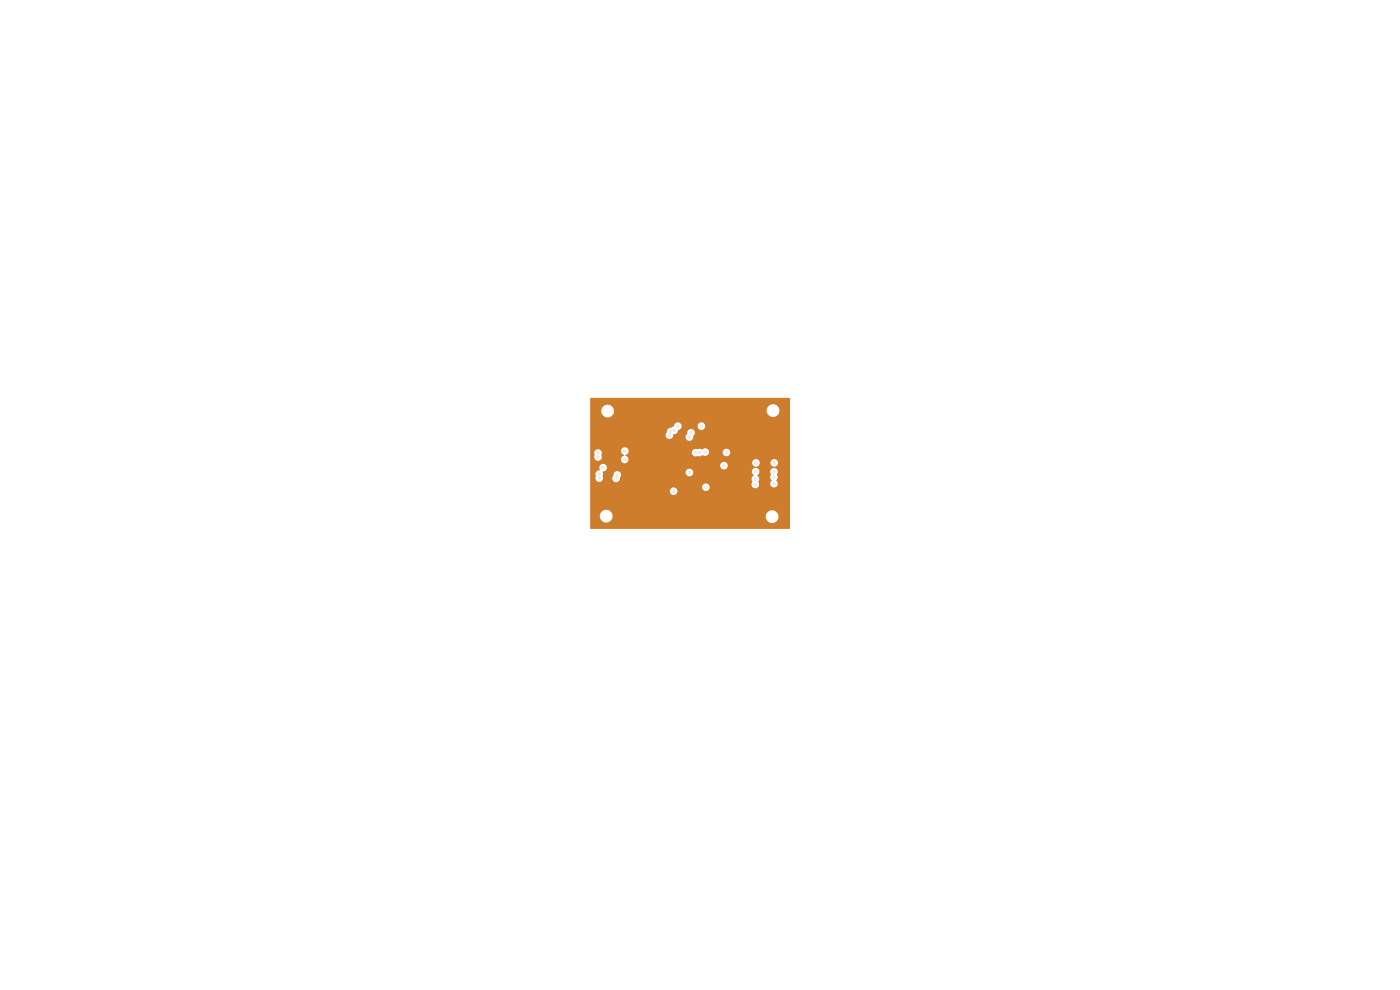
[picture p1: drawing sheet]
<svg xmlns="http://www.w3.org/2000/svg" width="297mm" height="210mm" viewBox="0 0 297 210" stroke-linecap="round" stroke-linejoin="round" font-family="sans-serif">
<g fill="#ececec" stroke="#ececec" stroke-width=".21">
<circle cx="143" cy="91.3" r=".3"/>
<circle cx="149.6" cy="95.9" r=".3"/>
<circle cx="137.2" cy="85" r=".3"/>
<circle cx="152.3" cy="103.2" r=".3"/>
<circle cx="139.2" cy="106.2" r=".3"/>
<circle cx="132" cy="109.2" r=".3"/>
<circle cx="141.4" cy="88.6" r=".3"/>
<circle cx="138.4" cy="86.2" r=".3"/>
<circle cx="151.6" cy="91.2" r=".3"/>
<circle cx="154.6" cy="87.4" r=".3"/>
<circle cx="159" cy="111.6" r=".3"/>
<circle cx="161.4" cy="108" r=".3"/>
<circle cx="160" cy="89.2" r=".3"/>
<circle cx="159.4" cy="89.2" r=".3"/>
<circle cx="127" cy="90.4" r=".3"/>
<circle cx="143.8" cy="86.2" r=".3"/>
<circle cx="138.6" cy="108" r=".3"/>
<circle cx="148.8" cy="110.4" r=".3"/>
<circle cx="137.2" cy="86.8" r=".3"/>
<circle cx="138.4" cy="88" r=".3"/>
<circle cx="126.4" cy="85" r=".3"/>
<circle cx="149.8" cy="85.6" r=".3"/>
<circle cx="139.8" cy="105.6" r=".3"/>
<circle cx="154.7" cy="103.2" r=".3"/>
<circle cx="134.4" cy="109.2" r=".3"/>
<circle cx="140.8" cy="89.2" r=".3"/>
<circle cx="155.8" cy="85" r=".3"/>
<circle cx="154.6" cy="89.2" r=".3"/>
<circle cx="151" cy="86.8" r=".3"/>
<circle cx="149.8" cy="88.6" r=".3"/>
<circle cx="139" cy="85" r=".3"/>
<circle cx="136.2" cy="110.4" r=".3"/>
<circle cx="161.2" cy="85" r=".3"/>
<circle cx="143.2" cy="86.2" r=".3"/>
<circle cx="129.6" cy="106.8" r=".3"/>
<circle cx="151.6" cy="88" r=".3"/>
<circle cx="141.6" cy="107.4" r=".3"/>
<circle cx="144.4" cy="88.6" r=".3"/>
<circle cx="133.8" cy="106.8" r=".3"/>
<circle cx="133.2" cy="109.8" r=".3"/>
<circle cx="127.6" cy="90.4" r=".3"/>
<circle cx="136.8" cy="111" r=".3"/>
<circle cx="140.2" cy="89.2" r=".3"/>
<circle cx="131.8" cy="86.2" r=".3"/>
<circle cx="134.8" cy="85" r=".3"/>
<circle cx="135" cy="107.4" r=".3"/>
<circle cx="159.6" cy="107.4" r=".3"/>
<circle cx="151" cy="87.4" r=".3"/>
<circle cx="135.4" cy="85" r=".3"/>
<circle cx="132.4" cy="88.6" r=".3"/>
<circle cx="156.4" cy="85" r=".3"/>
<circle cx="125.8" cy="85.6" r=".3"/>
<circle cx="136" cy="86.2" r=".3"/>
<circle cx="146.8" cy="85.6" r=".3"/>
<circle cx="166.7" cy="85" r=".3"/>
<circle cx="154" cy="85.6" r=".3"/>
<circle cx="156.4" cy="85.6" r=".3"/>
<circle cx="141.4" cy="86.8" r=".3"/>
<circle cx="134.8" cy="89.2" r=".3"/>
<circle cx="136" cy="88.6" r=".3"/>
<circle cx="156.4" cy="88" r=".3"/>
<circle cx="152.8" cy="91.2" r=".3"/>
<circle cx="145.8" cy="111" r=".3"/>
<circle cx="138.4" cy="89.2" r=".3"/>
<circle cx="152.4" cy="111" r=".3"/>
<circle cx="160.6" cy="86.8" r=".3"/>
<circle cx="149.2" cy="88.6" r=".3"/>
<circle cx="152.8" cy="87.4" r=".3"/>
<circle cx="137.8" cy="89.2" r=".3"/>
<circle cx="136.8" cy="109.8" r=".3"/>
<circle cx="146.4" cy="109.8" r=".3"/>
<circle cx="154.2" cy="111" r=".3"/>
<circle cx="155.4" cy="106.8" r=".3"/>
<circle cx="157" cy="86.2" r=".3"/>
<circle cx="149.2" cy="88" r=".3"/>
<circle cx="131.8" cy="86.8" r=".3"/>
<circle cx="153.5" cy="104.4" r=".3"/>
<circle cx="159" cy="110.4" r=".3"/>
<circle cx="145.6" cy="86.2" r=".3"/>
<circle cx="132.4" cy="85" r=".3"/>
<circle cx="132" cy="108" r=".3"/>
<circle cx="153.6" cy="106.2" r=".3"/>
<circle cx="136.8" cy="108.6" r=".3"/>
<circle cx="151.8" cy="109.2" r=".3"/>
<circle cx="151.6" cy="85" r=".3"/>
<circle cx="138" cy="107.4" r=".3"/>
<circle cx="137.4" cy="109.2" r=".3"/>
<circle cx="138" cy="108" r=".3"/>
<circle cx="158.2" cy="86.2" r=".3"/>
<circle cx="143.2" cy="89.2" r=".3"/>
<circle cx="154.8" cy="111.6" r=".3"/>
<circle cx="158.4" cy="108.6" r=".3"/>
<circle cx="149.8" cy="85" r=".3"/>
<circle cx="155.8" cy="91.2" r=".3"/>
<circle cx="154.8" cy="109.8" r=".3"/>
<circle cx="157.6" cy="89.2" r=".3"/>
<circle cx="133.6" cy="88.6" r=".3"/>
<circle cx="153.5" cy="102.6" r=".3"/>
<circle cx="156.6" cy="109.2" r=".3"/>
<circle cx="139.2" cy="106.8" r=".3"/>
<circle cx="133" cy="90.4" r=".3"/>
<circle cx="155.3" cy="104.4" r=".3"/>
<circle cx="151.2" cy="111" r=".3"/>
<circle cx="160.2" cy="109.2" r=".3"/>
<circle cx="125.8" cy="88" r=".3"/>
<circle cx="136" cy="89.8" r=".3"/>
<circle cx="137.4" cy="107.4" r=".3"/>
<circle cx="158.2" cy="86.8" r=".3"/>
<circle cx="150.4" cy="86.2" r=".3"/>
<circle cx="142.8" cy="109.2" r=".3"/>
<circle cx="137.8" cy="87.4" r=".3"/>
<circle cx="136" cy="87.4" r=".3"/>
<circle cx="160" cy="87.4" r=".3"/>
<circle cx="159.4" cy="85.6" r=".3"/>
<circle cx="152.9" cy="102.6" r=".3"/>
<circle cx="142" cy="87.4" r=".3"/>
<circle cx="142.6" cy="88" r=".3"/>
<circle cx="155.2" cy="91.2" r=".3"/>
<circle cx="160.2" cy="111.6" r=".3"/>
<circle cx="160.4" cy="92" r=".3"/>
<circle cx="143.2" cy="88.6" r=".3"/>
<circle cx="135.4" cy="90.4" r=".3"/>
<circle cx="152.2" cy="89.2" r=".3"/>
<circle cx="166.7" cy="88.6" r=".3"/>
<circle cx="159" cy="109.2" r=".3"/>
<circle cx="139" cy="87.4" r=".3"/>
<circle cx="147.6" cy="111" r=".3"/>
<circle cx="135" cy="109.2" r=".3"/>
<circle cx="145.6" cy="87.4" r=".3"/>
<circle cx="150.4" cy="87.4" r=".3"/>
<circle cx="165.8" cy="107.4" r=".3"/>
<circle cx="154" cy="86.2" r=".3"/>
<circle cx="157" cy="85" r=".3"/>
<circle cx="157.2" cy="109.8" r=".3"/>
<circle cx="143.2" cy="87.4" r=".3"/>
<circle cx="140.2" cy="88.6" r=".3"/>
<circle cx="152.9" cy="103.2" r=".3"/>
<circle cx="159.6" cy="110.4" r=".3"/>
<circle cx="166.7" cy="86.2" r=".3"/>
<circle cx="154" cy="85" r=".3"/>
<circle cx="143.2" cy="85" r=".3"/>
<circle cx="151.6" cy="89.2" r=".3"/>
<circle cx="139.8" cy="109.2" r=".3"/>
<circle cx="148.8" cy="111.6" r=".3"/>
<circle cx="157" cy="88" r=".3"/>
<circle cx="133.2" cy="111" r=".3"/>
<circle cx="156" cy="109.2" r=".3"/>
<circle cx="137.4" cy="106.2" r=".3"/>
<circle cx="160.6" cy="88.6" r=".3"/>
<circle cx="125.8" cy="89.2" r=".3"/>
<circle cx="145.8" cy="110.4" r=".3"/>
<circle cx="154.8" cy="108.6" r=".3"/>
<circle cx="151.8" cy="111.6" r=".3"/>
<circle cx="136" cy="85" r=".3"/>
<circle cx="134.2" cy="85" r=".3"/>
<circle cx="158.8" cy="85.6" r=".3"/>
<circle cx="155.1" cy="101.2" r=".3"/>
<circle cx="157.8" cy="108" r=".3"/>
<circle cx="138.4" cy="85" r=".3"/>
<circle cx="137.8" cy="86.2" r=".3"/>
<circle cx="132" cy="108.6" r=".3"/>
<circle cx="152.9" cy="105" r=".3"/>
<circle cx="143.4" cy="110.4" r=".3"/>
<circle cx="153.6" cy="109.2" r=".3"/>
<circle cx="154" cy="88" r=".3"/>
<circle cx="167" cy="108" r=".3"/>
<circle cx="150.4" cy="88" r=".3"/>
<circle cx="153.6" cy="106.8" r=".3"/>
<circle cx="139.6" cy="85.6" r=".3"/>
<circle cx="132" cy="111" r=".3"/>
<circle cx="142.6" cy="88.6" r=".3"/>
<circle cx="145.6" cy="85" r=".3"/>
<circle cx="136.6" cy="85.6" r=".3"/>
<circle cx="148" cy="87.4" r=".3"/>
<circle cx="155.2" cy="85.6" r=".3"/>
<circle cx="133" cy="85" r=".3"/>
<circle cx="146.2" cy="85.6" r=".3"/>
<circle cx="126.4" cy="90.4" r=".3"/>
<circle cx="141.4" cy="85.6" r=".3"/>
<circle cx="166.1" cy="85" r=".3"/>
<circle cx="160" cy="88.6" r=".3"/>
<circle cx="161.8" cy="85" r=".3"/>
<circle cx="137.8" cy="88.6" r=".3"/>
<circle cx="135.6" cy="111.6" r=".3"/>
<circle cx="126" cy="106.8" r=".3"/>
<circle cx="152.8" cy="85.6" r=".3"/>
<circle cx="145" cy="86.2" r=".3"/>
<circle cx="155.4" cy="111" r=".3"/>
<circle cx="156" cy="107.4" r=".3"/>
<circle cx="145" cy="88" r=".3"/>
<circle cx="132" cy="106.8" r=".3"/>
<circle cx="141.6" cy="111.6" r=".3"/>
<circle cx="152.2" cy="87.4" r=".3"/>
<circle cx="153.5" cy="105.6" r=".3"/>
<circle cx="137.4" cy="111" r=".3"/>
<circle cx="144.4" cy="88" r=".3"/>
<circle cx="138" cy="111.6" r=".3"/>
<circle cx="154.2" cy="106.8" r=".3"/>
<circle cx="142.8" cy="110.4" r=".3"/>
<circle cx="145" cy="87.4" r=".3"/>
<circle cx="142.6" cy="85" r=".3"/>
<circle cx="160.8" cy="109.2" r=".3"/>
<circle cx="157" cy="86.8" r=".3"/>
<circle cx="144.6" cy="111" r=".3"/>
<circle cx="138.4" cy="85.6" r=".3"/>
<circle cx="140.4" cy="109.2" r=".3"/>
<circle cx="139" cy="88" r=".3"/>
<circle cx="136.6" cy="85" r=".3"/>
<circle cx="149.2" cy="86.8" r=".3"/>
<circle cx="159" cy="109.8" r=".3"/>
<circle cx="155.4" cy="110.4" r=".3"/>
<circle cx="132.4" cy="86.8" r=".3"/>
<circle cx="141" cy="109.2" r=".3"/>
<circle cx="157.6" cy="85.6" r=".3"/>
<circle cx="159.6" cy="108" r=".3"/>
<circle cx="131.8" cy="88" r=".3"/>
<circle cx="132.6" cy="109.2" r=".3"/>
<circle cx="157.8" cy="109.8" r=".3"/>
<circle cx="143.8" cy="88.6" r=".3"/>
<circle cx="130.8" cy="106.8" r=".3"/>
<circle cx="156.6" cy="109.8" r=".3"/>
<circle cx="143.4" cy="109.8" r=".3"/>
<circle cx="136.6" cy="89.2" r=".3"/>
<circle cx="131.8" cy="85.6" r=".3"/>
<circle cx="138.6" cy="107.4" r=".3"/>
<circle cx="139.6" cy="86.8" r=".3"/>
<circle cx="148.2" cy="111" r=".3"/>
<circle cx="141.6" cy="106.2" r=".3"/>
<circle cx="153" cy="111.6" r=".3"/>
<circle cx="136" cy="88" r=".3"/>
<circle cx="132.4" cy="87.4" r=".3"/>
<circle cx="130.6" cy="89.8" r=".3"/>
<circle cx="147" cy="109.8" r=".3"/>
<circle cx="152.4" cy="110.4" r=".3"/>
<circle cx="136.8" cy="107.4" r=".3"/>
<circle cx="158.4" cy="109.2" r=".3"/>
<circle cx="154.2" cy="108" r=".3"/>
<circle cx="127" cy="85" r=".3"/>
<circle cx="153" cy="109.8" r=".3"/>
<circle cx="157.2" cy="110.4" r=".3"/>
<circle cx="159" cy="108.6" r=".3"/>
<circle cx="137.2" cy="96.5" r=".3"/>
<circle cx="154" cy="89.2" r=".3"/>
<circle cx="127.6" cy="91" r=".3"/>
<circle cx="139" cy="88.6" r=".3"/>
<circle cx="132.6" cy="108.6" r=".3"/>
<circle cx="135.6" cy="107.4" r=".3"/>
<circle cx="150.6" cy="110.4" r=".3"/>
<circle cx="144" cy="111" r=".3"/>
<circle cx="136.8" cy="106.2" r=".3"/>
<circle cx="166.4" cy="111.6" r=".3"/>
<circle cx="160.6" cy="86.2" r=".3"/>
<circle cx="156.4" cy="88.6" r=".3"/>
<circle cx="148.6" cy="89.2" r=".3"/>
<circle cx="125.8" cy="87.4" r=".3"/>
<circle cx="146.8" cy="88" r=".3"/>
<circle cx="154.8" cy="106.2" r=".3"/>
<circle cx="150.6" cy="109.8" r=".3"/>
<circle cx="158.8" cy="89.2" r=".3"/>
<circle cx="152.8" cy="88" r=".3"/>
<circle cx="135.4" cy="89.2" r=".3"/>
<circle cx="131.2" cy="85" r=".3"/>
<circle cx="157.2" cy="108.6" r=".3"/>
<circle cx="136.2" cy="106.8" r=".3"/>
<circle cx="157.6" cy="85" r=".3"/>
<circle cx="155.2" cy="87.4" r=".3"/>
<circle cx="159.4" cy="86.8" r=".3"/>
<circle cx="156" cy="109.8" r=".3"/>
<circle cx="155.3" cy="105.6" r=".3"/>
<circle cx="153.6" cy="110.4" r=".3"/>
<circle cx="155.7" cy="101.2" r=".3"/>
<circle cx="154.7" cy="105" r=".3"/>
<circle cx="126" cy="111" r=".3"/>
<circle cx="148.6" cy="86.2" r=".3"/>
<circle cx="167" cy="111.6" r=".3"/>
<circle cx="131.2" cy="90.4" r=".3"/>
<circle cx="145.2" cy="109.8" r=".3"/>
<circle cx="138.6" cy="109.2" r=".3"/>
<circle cx="137.2" cy="89.2" r=".3"/>
<circle cx="150.6" cy="111" r=".3"/>
<circle cx="136.2" cy="109.8" r=".3"/>
<circle cx="157.6" cy="88.6" r=".3"/>
<circle cx="128.2" cy="91" r=".3"/>
<circle cx="166.4" cy="108" r=".3"/>
<circle cx="151.2" cy="110.4" r=".3"/>
<circle cx="138.6" cy="111" r=".3"/>
<circle cx="135" cy="108" r=".3"/>
<circle cx="136.8" cy="106.8" r=".3"/>
<circle cx="155.4" cy="108.6" r=".3"/>
<circle cx="151.6" cy="85.6" r=".3"/>
<circle cx="130.2" cy="106.8" r=".3"/>
<circle cx="136.6" cy="88.6" r=".3"/>
<circle cx="132.4" cy="86.2" r=".3"/>
<circle cx="158.8" cy="86.2" r=".3"/>
<circle cx="146.2" cy="86.2" r=".3"/>
<circle cx="134.8" cy="89.8" r=".3"/>
<circle cx="156.4" cy="86.2" r=".3"/>
<circle cx="157" cy="89.2" r=".3"/>
<circle cx="156.6" cy="108.6" r=".3"/>
<circle cx="153.6" cy="109.8" r=".3"/>
<circle cx="144.4" cy="89.2" r=".3"/>
<circle cx="157.2" cy="111" r=".3"/>
<circle cx="159.6" cy="111" r=".3"/>
<circle cx="145" cy="85" r=".3"/>
<circle cx="148.2" cy="109.8" r=".3"/>
<circle cx="137.2" cy="86.2" r=".3"/>
<circle cx="149.8" cy="86.8" r=".3"/>
<circle cx="129.4" cy="90.4" r=".3"/>
<circle cx="157.8" cy="109.2" r=".3"/>
<circle cx="166.4" cy="107.4" r=".3"/>
<circle cx="139.8" cy="111" r=".3"/>
<circle cx="158.4" cy="111.6" r=".3"/>
<circle cx="160" cy="86.2" r=".3"/>
<circle cx="136.7" cy="101" r=".3"/>
<circle cx="132.4" cy="88" r=".3"/>
<circle cx="131.8" cy="89.2" r=".3"/>
<circle cx="133.6" cy="85" r=".3"/>
<circle cx="145" cy="86.8" r=".3"/>
<circle cx="139.2" cy="110.4" r=".3"/>
<circle cx="152.8" cy="86.2" r=".3"/>
<circle cx="154.2" cy="106.2" r=".3"/>
<circle cx="131.4" cy="108.6" r=".3"/>
<circle cx="126.6" cy="111.6" r=".3"/>
<circle cx="155.2" cy="88" r=".3"/>
<circle cx="152.4" cy="109.8" r=".3"/>
<circle cx="155.8" cy="86.8" r=".3"/>
<circle cx="134.2" cy="85.6" r=".3"/>
<circle cx="133.8" cy="107.4" r=".3"/>
<circle cx="167" cy="109.8" r=".3"/>
<circle cx="151" cy="85.6" r=".3"/>
<circle cx="131.4" cy="111" r=".3"/>
<circle cx="128.2" cy="90.4" r=".3"/>
<circle cx="131.2" cy="91" r=".3"/>
<circle cx="133.2" cy="111.6" r=".3"/>
<circle cx="138.6" cy="111.6" r=".3"/>
<circle cx="131.4" cy="107.4" r=".3"/>
<circle cx="151.6" cy="86.8" r=".3"/>
<circle cx="143.4" cy="109.2" r=".3"/>
<circle cx="134.4" cy="107.4" r=".3"/>
<circle cx="146.8" cy="86.2" r=".3"/>
<circle cx="141.4" cy="87.4" r=".3"/>
<circle cx="154.1" cy="103.8" r=".3"/>
<circle cx="155.8" cy="86.2" r=".3"/>
<circle cx="154.1" cy="105" r=".3"/>
<circle cx="155.7" cy="98.2" r=".3"/>
<circle cx="142" cy="85.6" r=".3"/>
<circle cx="167" cy="111" r=".3"/>
<circle cx="133" cy="85.6" r=".3"/>
<circle cx="155.7" cy="100.6" r=".3"/>
<circle cx="156.4" cy="86.8" r=".3"/>
<circle cx="154.2" cy="110.4" r=".3"/>
<circle cx="134.8" cy="85.6" r=".3"/>
<circle cx="140.4" cy="105.6" r=".3"/>
<circle cx="161.2" cy="87.4" r=".3"/>
<circle cx="146.4" cy="111.6" r=".3"/>
<circle cx="137.8" cy="85" r=".3"/>
<circle cx="155.2" cy="85" r=".3"/>
<circle cx="136.6" cy="86.2" r=".3"/>
<circle cx="160.6" cy="88" r=".3"/>
<circle cx="130.6" cy="91" r=".3"/>
<circle cx="138" cy="111" r=".3"/>
<circle cx="127" cy="89.8" r=".3"/>
<circle cx="156" cy="108" r=".3"/>
<circle cx="138.4" cy="87.4" r=".3"/>
<circle cx="141" cy="107.4" r=".3"/>
<circle cx="128.8" cy="91" r=".3"/>
<circle cx="142.6" cy="86.8" r=".3"/>
<circle cx="149.4" cy="111.6" r=".3"/>
<circle cx="133.6" cy="86.8" r=".3"/>
<circle cx="139.2" cy="108.6" r=".3"/>
<circle cx="148.2" cy="110.4" r=".3"/>
<circle cx="157.6" cy="86.8" r=".3"/>
<circle cx="160.8" cy="109.8" r=".3"/>
<circle cx="145.8" cy="109.8" r=".3"/>
<circle cx="125.8" cy="86.2" r=".3"/>
<circle cx="160.8" cy="107.4" r=".3"/>
<circle cx="157.6" cy="88" r=".3"/>
<circle cx="146.2" cy="87.4" r=".3"/>
<circle cx="148.2" cy="109.2" r=".3"/>
<circle cx="133.6" cy="89.8" r=".3"/>
<circle cx="137.4" cy="109.8" r=".3"/>
<circle cx="139.2" cy="109.2" r=".3"/>
<circle cx="153.6" cy="108" r=".3"/>
<circle cx="151.2" cy="92.4" r=".3"/>
<circle cx="139" cy="89.2" r=".3"/>
<circle cx="133" cy="89.2" r=".3"/>
<circle cx="149.4" cy="109.8" r=".3"/>
<circle cx="154.8" cy="110.4" r=".3"/>
<circle cx="156" cy="111" r=".3"/>
<circle cx="141.6" cy="106.8" r=".3"/>
<circle cx="160.2" cy="107.4" r=".3"/>
<circle cx="131.8" cy="91" r=".3"/>
<circle cx="150.4" cy="85" r=".3"/>
<circle cx="151" cy="88.6" r=".3"/>
<circle cx="154.6" cy="88.6" r=".3"/>
<circle cx="140.4" cy="107.4" r=".3"/>
<circle cx="130.8" cy="107.4" r=".3"/>
<circle cx="149.2" cy="85" r=".3"/>
<circle cx="147" cy="109.2" r=".3"/>
<circle cx="145.2" cy="111.6" r=".3"/>
<circle cx="134.2" cy="90.4" r=".3"/>
<circle cx="141.4" cy="85" r=".3"/>
<circle cx="139.2" cy="105.6" r=".3"/>
<circle cx="135" cy="106.8" r=".3"/>
<circle cx="135" cy="108.6" r=".3"/>
<circle cx="134.2" cy="89.8" r=".3"/>
<circle cx="153.4" cy="89.2" r=".3"/>
<circle cx="157.8" cy="108.6" r=".3"/>
<circle cx="148.6" cy="88.6" r=".3"/>
<circle cx="143.8" cy="87.4" r=".3"/>
<circle cx="158.4" cy="110.4" r=".3"/>
<circle cx="133.2" cy="110.4" r=".3"/>
<circle cx="136.2" cy="107.4" r=".3"/>
<circle cx="155.7" cy="100" r=".3"/>
<circle cx="135.6" cy="111" r=".3"/>
<circle cx="161.2" cy="86.2" r=".3"/>
<circle cx="146.2" cy="89.2" r=".3"/>
<circle cx="151" cy="85" r=".3"/>
<circle cx="156" cy="111.6" r=".3"/>
<circle cx="136.6" cy="88" r=".3"/>
<circle cx="148.8" cy="109.8" r=".3"/>
<circle cx="150" cy="111" r=".3"/>
<circle cx="148.6" cy="85" r=".3"/>
<circle cx="158.2" cy="85.6" r=".3"/>
<circle cx="139.2" cy="111" r=".3"/>
<circle cx="140.8" cy="88" r=".3"/>
<circle cx="135.4" cy="85.6" r=".3"/>
<circle cx="145.6" cy="86.8" r=".3"/>
<circle cx="133" cy="89.8" r=".3"/>
<circle cx="125.8" cy="86.8" r=".3"/>
<circle cx="132" cy="107.4" r=".3"/>
<circle cx="159.4" cy="87.4" r=".3"/>
<circle cx="136.8" cy="108" r=".3"/>
<circle cx="152.3" cy="103.8" r=".3"/>
<circle cx="133.2" cy="106.8" r=".3"/>
<circle cx="140.4" cy="109.8" r=".3"/>
<circle cx="140.8" cy="85" r=".3"/>
<circle cx="139.2" cy="109.8" r=".3"/>
<circle cx="145.2" cy="111" r=".3"/>
<circle cx="144.6" cy="109.2" r=".3"/>
<circle cx="135.6" cy="106.8" r=".3"/>
<circle cx="147.4" cy="87.4" r=".3"/>
<circle cx="167" cy="110.4" r=".3"/>
<circle cx="145.8" cy="109.2" r=".3"/>
<circle cx="130.8" cy="111.6" r=".3"/>
<circle cx="158.2" cy="87.4" r=".3"/>
<circle cx="136.2" cy="111" r=".3"/>
<circle cx="152.2" cy="85" r=".3"/>
<circle cx="154.8" cy="107.4" r=".3"/>
<circle cx="142" cy="85" r=".3"/>
<circle cx="138.6" cy="106.2" r=".3"/>
<circle cx="136.8" cy="109.2" r=".3"/>
<circle cx="153.4" cy="86.2" r=".3"/>
<circle cx="139.6" cy="89.2" r=".3"/>
<circle cx="136.6" cy="87.4" r=".3"/>
<circle cx="158.8" cy="88" r=".3"/>
<circle cx="150" cy="109.8" r=".3"/>
<circle cx="165.8" cy="111.6" r=".3"/>
<circle cx="146.8" cy="85" r=".3"/>
<circle cx="134.2" cy="86.2" r=".3"/>
<circle cx="153.4" cy="91.2" r=".3"/>
<circle cx="130.6" cy="90.4" r=".3"/>
<circle cx="131.2" cy="89.8" r=".3"/>
<circle cx="133.6" cy="87.4" r=".3"/>
<circle cx="142.2" cy="110.4" r=".3"/>
<circle cx="155.8" cy="89.2" r=".3"/>
<circle cx="159.4" cy="88.6" r=".3"/>
<circle cx="141.6" cy="108.6" r=".3"/>
<circle cx="148" cy="85.6" r=".3"/>
<circle cx="135.6" cy="109.2" r=".3"/>
<circle cx="151.6" cy="86.2" r=".3"/>
<circle cx="138" cy="106.8" r=".3"/>
<circle cx="161.2" cy="85.6" r=".3"/>
<circle cx="143.8" cy="85" r=".3"/>
<circle cx="132.6" cy="109.8" r=".3"/>
<circle cx="139" cy="86.8" r=".3"/>
<circle cx="141" cy="111.6" r=".3"/>
<circle cx="127.2" cy="106.8" r=".3"/>
<circle cx="133.6" cy="88" r=".3"/>
<circle cx="157.2" cy="108" r=".3"/>
<circle cx="161.4" cy="111" r=".3"/>
<circle cx="126.4" cy="88.6" r=".3"/>
<circle cx="137.4" cy="106.8" r=".3"/>
<circle cx="161.8" cy="89.2" r=".3"/>
<circle cx="151.2" cy="111.6" r=".3"/>
<circle cx="150" cy="111.6" r=".3"/>
<circle cx="139.8" cy="108.6" r=".3"/>
<circle cx="150.4" cy="88.6" r=".3"/>
<circle cx="134.4" cy="111.6" r=".3"/>
<circle cx="149.8" cy="88" r=".3"/>
<circle cx="134.8" cy="86.8" r=".3"/>
<circle cx="146.2" cy="85" r=".3"/>
<circle cx="151" cy="89.2" r=".3"/>
<circle cx="161.2" cy="88" r=".3"/>
<circle cx="154.8" cy="109.2" r=".3"/>
<circle cx="155.3" cy="105" r=".3"/>
<circle cx="137.8" cy="88" r=".3"/>
<circle cx="134.2" cy="86.8" r=".3"/>
<circle cx="150.4" cy="86.8" r=".3"/>
<circle cx="142.8" cy="109.8" r=".3"/>
<circle cx="153.5" cy="103.8" r=".3"/>
<circle cx="154.5" cy="101.2" r=".3"/>
<circle cx="143.8" cy="86.8" r=".3"/>
<circle cx="132" cy="109.8" r=".3"/>
<circle cx="150.6" cy="109.2" r=".3"/>
<circle cx="136.2" cy="109.2" r=".3"/>
<circle cx="154.5" cy="100.6" r=".3"/>
<circle cx="142.6" cy="85.6" r=".3"/>
<circle cx="144" cy="110.4" r=".3"/>
<circle cx="134.8" cy="86.2" r=".3"/>
<circle cx="161.2" cy="86.8" r=".3"/>
<circle cx="131.4" cy="111.6" r=".3"/>
<circle cx="156.4" cy="87.4" r=".3"/>
<circle cx="160.6" cy="85" r=".3"/>
<circle cx="126.4" cy="89.2" r=".3"/>
<circle cx="160.6" cy="87.4" r=".3"/>
<circle cx="142.2" cy="109.8" r=".3"/>
<circle cx="153.4" cy="88.6" r=".3"/>
<circle cx="134.4" cy="111" r=".3"/>
<circle cx="126.4" cy="85.6" r=".3"/>
<circle cx="161.4" cy="107.4" r=".3"/>
<circle cx="147.4" cy="85" r=".3"/>
<circle cx="133.2" cy="107.4" r=".3"/>
<circle cx="156" cy="108.6" r=".3"/>
<circle cx="133.6" cy="85.6" r=".3"/>
<circle cx="151" cy="86.2" r=".3"/>
<circle cx="144.4" cy="85" r=".3"/>
<circle cx="159" cy="111" r=".3"/>
<circle cx="134.8" cy="90.4" r=".3"/>
<circle cx="153.4" cy="85" r=".3"/>
<circle cx="159.4" cy="85" r=".3"/>
<circle cx="155.4" cy="108" r=".3"/>
<circle cx="137.2" cy="88" r=".3"/>
<circle cx="152.2" cy="85.6" r=".3"/>
<circle cx="136" cy="89.2" r=".3"/>
<circle cx="132" cy="110.4" r=".3"/>
<circle cx="136" cy="86.8" r=".3"/>
<circle cx="153.4" cy="86.8" r=".3"/>
<circle cx="141.6" cy="109.8" r=".3"/>
<circle cx="153" cy="92.4" r=".3"/>
<circle cx="135" cy="110.4" r=".3"/>
<circle cx="139.6" cy="88" r=".3"/>
<circle cx="133" cy="91" r=".3"/>
<circle cx="148" cy="86.8" r=".3"/>
<circle cx="133.8" cy="109.2" r=".3"/>
<circle cx="146.4" cy="111" r=".3"/>
<circle cx="135.4" cy="86.8" r=".3"/>
<circle cx="141" cy="105.6" r=".3"/>
<circle cx="155.1" cy="98.2" r=".3"/>
<circle cx="142" cy="88" r=".3"/>
<circle cx="145.6" cy="88.6" r=".3"/>
<circle cx="153.5" cy="105" r=".3"/>
<circle cx="139.2" cy="111.6" r=".3"/>
<circle cx="166.4" cy="108.6" r=".3"/>
<circle cx="152.9" cy="105.6" r=".3"/>
<circle cx="154.1" cy="105.6" r=".3"/>
<circle cx="156.6" cy="111.6" r=".3"/>
<circle cx="154.8" cy="106.8" r=".3"/>
<circle cx="132.4" cy="89.8" r=".3"/>
<circle cx="126.6" cy="107.4" r=".3"/>
<circle cx="131.8" cy="87.4" r=".3"/>
<circle cx="132.6" cy="108" r=".3"/>
<circle cx="126.4" cy="89.8" r=".3"/>
<circle cx="161.4" cy="111.6" r=".3"/>
<circle cx="133.6" cy="90.4" r=".3"/>
<circle cx="155.8" cy="87.4" r=".3"/>
<circle cx="138.6" cy="110.4" r=".3"/>
<circle cx="144" cy="109.2" r=".3"/>
<circle cx="130" cy="91" r=".3"/>
<circle cx="146.8" cy="88.6" r=".3"/>
<circle cx="137.4" cy="108.6" r=".3"/>
<circle cx="126.4" cy="91" r=".3"/>
<circle cx="150.4" cy="85.6" r=".3"/>
<circle cx="156.6" cy="110.4" r=".3"/>
<circle cx="160.2" cy="110.4" r=".3"/>
<circle cx="154.2" cy="108.6" r=".3"/>
<circle cx="139" cy="86.2" r=".3"/>
<circle cx="158.2" cy="88" r=".3"/>
<circle cx="141" cy="111" r=".3"/>
<circle cx="144.4" cy="86.2" r=".3"/>
<circle cx="141.4" cy="86.2" r=".3"/>
<circle cx="150.6" cy="92.4" r=".3"/>
<circle cx="160" cy="85" r=".3"/>
<circle cx="154.7" cy="104.4" r=".3"/>
<circle cx="134.4" cy="108.6" r=".3"/>
<circle cx="155.1" cy="100" r=".3"/>
<circle cx="146.4" cy="110.4" r=".3"/>
<circle cx="131.4" cy="109.8" r=".3"/>
<circle cx="160.8" cy="111" r=".3"/>
<circle cx="133" cy="88" r=".3"/>
<circle cx="161.2" cy="88.6" r=".3"/>
<circle cx="131.8" cy="89.8" r=".3"/>
<circle cx="158.8" cy="87.4" r=".3"/>
<circle cx="140.8" cy="85.6" r=".3"/>
<circle cx="148.6" cy="88" r=".3"/>
<circle cx="159.4" cy="88" r=".3"/>
<circle cx="143.4" cy="111.6" r=".3"/>
<circle cx="139.8" cy="106.2" r=".3"/>
<circle cx="148" cy="86.2" r=".3"/>
<circle cx="156.6" cy="111" r=".3"/>
<circle cx="134.2" cy="87.4" r=".3"/>
<circle cx="146.4" cy="109.2" r=".3"/>
<circle cx="155.8" cy="85.6" r=".3"/>
<circle cx="142.6" cy="89.2" r=".3"/>
<circle cx="152.8" cy="86.8" r=".3"/>
<circle cx="166" cy="89.2" r=".3"/>
<circle cx="127.6" cy="89.8" r=".3"/>
<circle cx="131.4" cy="108" r=".3"/>
<circle cx="147.4" cy="86.2" r=".3"/>
<circle cx="146.8" cy="89.2" r=".3"/>
<circle cx="157" cy="88.6" r=".3"/>
<circle cx="154.2" cy="109.8" r=".3"/>
<circle cx="157.2" cy="109.2" r=".3"/>
<circle cx="139.2" cy="107.4" r=".3"/>
<circle cx="141.6" cy="111" r=".3"/>
<circle cx="133.6" cy="86.2" r=".3"/>
<circle cx="155.2" cy="86.2" r=".3"/>
<circle cx="132.6" cy="107.4" r=".3"/>
<circle cx="140.4" cy="108.6" r=".3"/>
<circle cx="138" cy="109.2" r=".3"/>
<circle cx="160.6" cy="89.2" r=".3"/>
<circle cx="125.8" cy="88.6" r=".3"/>
<circle cx="152.2" cy="88.6" r=".3"/>
<circle cx="154.2" cy="107.4" r=".3"/>
<circle cx="149.8" cy="86.2" r=".3"/>
<circle cx="145.6" cy="89.2" r=".3"/>
<circle cx="141" cy="106.8" r=".3"/>
<circle cx="134.4" cy="106.8" r=".3"/>
<circle cx="155.1" cy="100.6" r=".3"/>
<circle cx="144.4" cy="85.6" r=".3"/>
<circle cx="155.4" cy="106.2" r=".3"/>
<circle cx="153.5" cy="103.2" r=".3"/>
<circle cx="154" cy="88.6" r=".3"/>
<circle cx="154.8" cy="108" r=".3"/>
<circle cx="151" cy="91.2" r=".3"/>
<circle cx="158.8" cy="85" r=".3"/>
<circle cx="148" cy="89.2" r=".3"/>
<circle cx="158.2" cy="89.2" r=".3"/>
<circle cx="150" cy="109.2" r=".3"/>
<circle cx="148.8" cy="111" r=".3"/>
<circle cx="141.4" cy="88" r=".3"/>
<circle cx="145.8" cy="111.6" r=".3"/>
<circle cx="157.8" cy="110.4" r=".3"/>
<circle cx="147.4" cy="88" r=".3"/>
<circle cx="153.6" cy="111.6" r=".3"/>
<circle cx="155.7" cy="98.8" r=".3"/>
<circle cx="154" cy="86.8" r=".3"/>
<circle cx="154.1" cy="102.6" r=".3"/>
<circle cx="140.4" cy="111" r=".3"/>
<circle cx="142.2" cy="111.6" r=".3"/>
<circle cx="154.6" cy="85" r=".3"/>
<circle cx="151.6" cy="88.6" r=".3"/>
<circle cx="142" cy="86.8" r=".3"/>
<circle cx="154.7" cy="105.6" r=".3"/>
<circle cx="133" cy="88.6" r=".3"/>
<circle cx="137.2" cy="85.6" r=".3"/>
<circle cx="132.4" cy="91" r=".3"/>
<circle cx="128.8" cy="90.4" r=".3"/>
<circle cx="147" cy="110.4" r=".3"/>
<circle cx="147.6" cy="110.4" r=".3"/>
<circle cx="132.4" cy="90.4" r=".3"/>
<circle cx="155.4" cy="111.6" r=".3"/>
<circle cx="148" cy="85" r=".3"/>
<circle cx="166.7" cy="89.2" r=".3"/>
<circle cx="153.4" cy="88" r=".3"/>
<circle cx="152.2" cy="91.2" r=".3"/>
<circle cx="140.2" cy="87.4" r=".3"/>
<circle cx="139.8" cy="109.8" r=".3"/>
<circle cx="139.6" cy="85" r=".3"/>
<circle cx="152.4" cy="92.4" r=".3"/>
<circle cx="125.8" cy="89.8" r=".3"/>
<circle cx="146.2" cy="88" r=".3"/>
<circle cx="136.2" cy="108" r=".3"/>
<circle cx="125.8" cy="85" r=".3"/>
<circle cx="133.2" cy="108" r=".3"/>
<circle cx="141" cy="106.2" r=".3"/>
<circle cx="138" cy="109.8" r=".3"/>
<circle cx="155.3" cy="103.8" r=".3"/>
<circle cx="142.2" cy="109.2" r=".3"/>
<circle cx="133.8" cy="110.4" r=".3"/>
<circle cx="155.8" cy="88.6" r=".3"/>
<circle cx="152.2" cy="86.2" r=".3"/>
<circle cx="126" cy="107.4" r=".3"/>
<circle cx="140.2" cy="86.8" r=".3"/>
<circle cx="148" cy="88" r=".3"/>
<circle cx="140.8" cy="86.2" r=".3"/>
<circle cx="127" cy="91" r=".3"/>
<circle cx="154.6" cy="86.8" r=".3"/>
<circle cx="141" cy="110.4" r=".3"/>
<circle cx="131.4" cy="109.2" r=".3"/>
<circle cx="151.8" cy="111" r=".3"/>
<circle cx="143.4" cy="111" r=".3"/>
<circle cx="152.4" cy="109.2" r=".3"/>
<circle cx="140.4" cy="106.2" r=".3"/>
<circle cx="154.7" cy="103.8" r=".3"/>
<circle cx="132.4" cy="89.2" r=".3"/>
<circle cx="134.4" cy="109.8" r=".3"/>
<circle cx="131.8" cy="90.4" r=".3"/>
<circle cx="157.8" cy="111" r=".3"/>
<circle cx="142.6" cy="86.2" r=".3"/>
<circle cx="150.6" cy="111.6" r=".3"/>
<circle cx="140.2" cy="85.6" r=".3"/>
<circle cx="141.6" cy="105.6" r=".3"/>
<circle cx="142.6" cy="87.4" r=".3"/>
<circle cx="157.8" cy="111.6" r=".3"/>
<circle cx="167" cy="109.2" r=".3"/>
<circle cx="155.2" cy="88.6" r=".3"/>
<circle cx="152.8" cy="89.2" r=".3"/>
<circle cx="148.6" cy="85.6" r=".3"/>
<circle cx="152.9" cy="104.4" r=".3"/>
<circle cx="134.2" cy="88" r=".3"/>
<circle cx="139.6" cy="86.2" r=".3"/>
<circle cx="134.4" cy="110.4" r=".3"/>
<circle cx="146.8" cy="87.4" r=".3"/>
<circle cx="137.2" cy="87.4" r=".3"/>
<circle cx="137.7" cy="104.4" r=".3"/>
<circle cx="153" cy="110.4" r=".3"/>
<circle cx="145" cy="88.6" r=".3"/>
<circle cx="160.8" cy="111.6" r=".3"/>
<circle cx="140.8" cy="86.8" r=".3"/>
<circle cx="156" cy="110.4" r=".3"/>
<circle cx="139.6" cy="87.4" r=".3"/>
<circle cx="157" cy="87.4" r=".3"/>
<circle cx="149.4" cy="110.4" r=".3"/>
<circle cx="160.8" cy="108" r=".3"/>
<circle cx="132" cy="111.6" r=".3"/>
<circle cx="142.2" cy="111" r=".3"/>
<circle cx="133.8" cy="109.8" r=".3"/>
<circle cx="133.8" cy="108.6" r=".3"/>
<circle cx="151" cy="88" r=".3"/>
<circle cx="158.4" cy="109.8" r=".3"/>
<circle cx="160.8" cy="110.4" r=".3"/>
<circle cx="153.4" cy="87.4" r=".3"/>
<circle cx="151.2" cy="109.8" r=".3"/>
<circle cx="155.4" cy="109.8" r=".3"/>
<circle cx="151.2" cy="109.2" r=".3"/>
<circle cx="155.7" cy="99.4" r=".3"/>
<circle cx="136.6" cy="86.8" r=".3"/>
<circle cx="167" cy="108.6" r=".3"/>
<circle cx="135" cy="109.8" r=".3"/>
<circle cx="152.8" cy="85" r=".3"/>
<circle cx="159.6" cy="109.2" r=".3"/>
<circle cx="147.6" cy="109.8" r=".3"/>
<circle cx="141.4" cy="89.2" r=".3"/>
<circle cx="138.6" cy="108.6" r=".3"/>
<circle cx="135" cy="111.6" r=".3"/>
<circle cx="143.2" cy="88" r=".3"/>
<circle cx="144" cy="109.8" r=".3"/>
<circle cx="147.4" cy="86.8" r=".3"/>
<circle cx="133.2" cy="108.6" r=".3"/>
<circle cx="153.6" cy="111" r=".3"/>
<circle cx="140.2" cy="85" r=".3"/>
<circle cx="135.6" cy="109.8" r=".3"/>
<circle cx="135.6" cy="110.4" r=".3"/>
<circle cx="152.9" cy="103.8" r=".3"/>
<circle cx="138.6" cy="109.8" r=".3"/>
<circle cx="149.8" cy="89.2" r=".3"/>
<circle cx="133.2" cy="109.2" r=".3"/>
<circle cx="144.6" cy="111.6" r=".3"/>
<circle cx="135.6" cy="108" r=".3"/>
<circle cx="157.6" cy="86.2" r=".3"/>
<circle cx="154.6" cy="86.2" r=".3"/>
<circle cx="149.2" cy="86.2" r=".3"/>
<circle cx="154.1" cy="104.4" r=".3"/>
<circle cx="126.6" cy="106.8" r=".3"/>
<circle cx="131.8" cy="85" r=".3"/>
<circle cx="134.2" cy="89.2" r=".3"/>
<circle cx="130" cy="89.8" r=".3"/>
<circle cx="148.2" cy="111.6" r=".3"/>
<circle cx="139.8" cy="107.4" r=".3"/>
<circle cx="147.6" cy="111.6" r=".3"/>
<circle cx="136.8" cy="111.6" r=".3"/>
<circle cx="136.8" cy="110.4" r=".3"/>
<circle cx="158.4" cy="108" r=".3"/>
<circle cx="145" cy="85.6" r=".3"/>
<circle cx="160.6" cy="85.6" r=".3"/>
<circle cx="152.3" cy="104.4" r=".3"/>
<circle cx="134.8" cy="88.6" r=".3"/>
<circle cx="156.6" cy="107.4" r=".3"/>
<circle cx="156.6" cy="108" r=".3"/>
<circle cx="132.6" cy="110.4" r=".3"/>
<circle cx="160.2" cy="108" r=".3"/>
<circle cx="148.6" cy="86.8" r=".3"/>
<circle cx="158.2" cy="85" r=".3"/>
<circle cx="132.6" cy="111.6" r=".3"/>
<circle cx="153.6" cy="107.4" r=".3"/>
<circle cx="153" cy="109.2" r=".3"/>
<circle cx="160.2" cy="108.6" r=".3"/>
<circle cx="140.2" cy="88" r=".3"/>
<circle cx="135.4" cy="88.6" r=".3"/>
<circle cx="149.2" cy="85.6" r=".3"/>
<circle cx="153.4" cy="85.6" r=".3"/>
<circle cx="142" cy="89.2" r=".3"/>
<circle cx="141" cy="109.8" r=".3"/>
<circle cx="145" cy="89.2" r=".3"/>
<circle cx="140.4" cy="110.4" r=".3"/>
<circle cx="148" cy="88.6" r=".3"/>
<circle cx="151.6" cy="87.4" r=".3"/>
<circle cx="166.4" cy="111" r=".3"/>
<circle cx="138" cy="108.6" r=".3"/>
<circle cx="125.8" cy="91" r=".3"/>
<circle cx="136.2" cy="108.6" r=".3"/>
<circle cx="144.4" cy="87.4" r=".3"/>
<circle cx="137.2" cy="88.6" r=".3"/>
<circle cx="138.4" cy="86.8" r=".3"/>
<circle cx="143.8" cy="88" r=".3"/>
<circle cx="157.2" cy="111.6" r=".3"/>
<circle cx="133.8" cy="108" r=".3"/>
<circle cx="138" cy="110.4" r=".3"/>
<circle cx="147.4" cy="88.6" r=".3"/>
<circle cx="143.2" cy="85.6" r=".3"/>
<circle cx="152.3" cy="105" r=".3"/>
<circle cx="135.6" cy="108.6" r=".3"/>
<circle cx="137.4" cy="108" r=".3"/>
<circle cx="140.4" cy="106.8" r=".3"/>
<circle cx="133" cy="87.4" r=".3"/>
<circle cx="147" cy="111" r=".3"/>
<circle cx="138.6" cy="106.8" r=".3"/>
<circle cx="146.8" cy="86.8" r=".3"/>
<circle cx="131.4" cy="110.4" r=".3"/>
<circle cx="159.6" cy="111.6" r=".3"/>
<circle cx="137.8" cy="85.6" r=".3"/>
<circle cx="137.4" cy="110.4" r=".3"/>
<circle cx="139.8" cy="110.4" r=".3"/>
<circle cx="155.1" cy="99.4" r=".3"/>
<circle cx="135.4" cy="86.2" r=".3"/>
<circle cx="134.8" cy="88" r=".3"/>
<circle cx="132.6" cy="106.8" r=".3"/>
<circle cx="138" cy="106.2" r=".3"/>
<circle cx="133.6" cy="89.2" r=".3"/>
<circle cx="154.6" cy="91.2" r=".3"/>
<circle cx="135.4" cy="89.8" r=".3"/>
<circle cx="136" cy="91" r=".3"/>
<circle cx="157.6" cy="87.4" r=".3"/>
<circle cx="158.2" cy="88.6" r=".3"/>
<circle cx="144.6" cy="110.4" r=".3"/>
<circle cx="148.8" cy="109.2" r=".3"/>
<circle cx="153" cy="111" r=".3"/>
<circle cx="154.8" cy="111" r=".3"/>
<circle cx="133.8" cy="111" r=".3"/>
<circle cx="147.6" cy="109.2" r=".3"/>
<circle cx="152.4" cy="111.6" r=".3"/>
<circle cx="141.6" cy="108" r=".3"/>
<circle cx="135.4" cy="87.4" r=".3"/>
<circle cx="139.6" cy="88.6" r=".3"/>
<circle cx="160.8" cy="108.6" r=".3"/>
<circle cx="156.4" cy="89.2" r=".3"/>
<circle cx="154" cy="91.2" r=".3"/>
<circle cx="139.8" cy="108" r=".3"/>
<circle cx="139" cy="85.6" r=".3"/>
<circle cx="155.4" cy="109.2" r=".3"/>
<circle cx="132.6" cy="111" r=".3"/>
<circle cx="140.4" cy="108" r=".3"/>
<circle cx="133.8" cy="111.6" r=".3"/>
<circle cx="147.4" cy="89.2" r=".3"/>
<circle cx="130" cy="90.4" r=".3"/>
<circle cx="159.4" cy="86.2" r=".3"/>
<circle cx="167" cy="107.4" r=".3"/>
<circle cx="138.4" cy="88.6" r=".3"/>
<circle cx="134.8" cy="87.4" r=".3"/>
<circle cx="140.8" cy="88.6" r=".3"/>
<circle cx="134.4" cy="108" r=".3"/>
<circle cx="152.2" cy="86.8" r=".3"/>
<circle cx="160" cy="88" r=".3"/>
<circle cx="152.8" cy="88.6" r=".3"/>
<circle cx="158.8" cy="86.8" r=".3"/>
<circle cx="125.8" cy="90.4" r=".3"/>
<circle cx="146.2" cy="88.6" r=".3"/>
<circle cx="142.8" cy="111.6" r=".3"/>
<circle cx="151.8" cy="109.8" r=".3"/>
<circle cx="145.6" cy="85.6" r=".3"/>
<circle cx="143.8" cy="89.2" r=".3"/>
<circle cx="146.2" cy="86.8" r=".3"/>
<circle cx="133" cy="86.8" r=".3"/>
<circle cx="135.4" cy="88" r=".3"/>
<circle cx="155.1" cy="98.8" r=".3"/>
<circle cx="160.2" cy="109.8" r=".3"/>
<circle cx="142.8" cy="111" r=".3"/>
<circle cx="166.7" cy="88" r=".3"/>
<circle cx="134.2" cy="88.6" r=".3"/>
<circle cx="148.6" cy="87.4" r=".3"/>
<circle cx="159.6" cy="108.6" r=".3"/>
<circle cx="155.2" cy="89.2" r=".3"/>
<circle cx="160" cy="85.6" r=".3"/>
<circle cx="150.4" cy="89.2" r=".3"/>
<circle cx="139.8" cy="106.8" r=".3"/>
<circle cx="149.2" cy="87.4" r=".3"/>
<circle cx="137.8" cy="86.8" r=".3"/>
<circle cx="155.2" cy="86.8" r=".3"/>
<circle cx="131.8" cy="88.6" r=".3"/>
<circle cx="157" cy="85.6" r=".3"/>
<circle cx="143.2" cy="86.8" r=".3"/>
<circle cx="160" cy="86.8" r=".3"/>
<circle cx="149.4" cy="111" r=".3"/>
<circle cx="141" cy="108.6" r=".3"/>
<circle cx="145.2" cy="109.2" r=".3"/>
<circle cx="149.8" cy="87.4" r=".3"/>
<circle cx="144.6" cy="109.8" r=".3"/>
<circle cx="149.4" cy="109.2" r=".3"/>
<circle cx="159" cy="108" r=".3"/>
<circle cx="145.2" cy="110.4" r=".3"/>
<circle cx="151.8" cy="110.4" r=".3"/>
<circle cx="153.6" cy="108.6" r=".3"/>
<circle cx="142" cy="88.6" r=".3"/>
<circle cx="152.2" cy="88" r=".3"/>
<circle cx="142" cy="86.2" r=".3"/>
<circle cx="126" cy="108" r=".3"/>
<circle cx="155.8" cy="88" r=".3"/>
<circle cx="154.6" cy="88" r=".3"/>
<circle cx="154.1" cy="103.2" r=".3"/>
<circle cx="139.8" cy="111.6" r=".3"/>
<circle cx="140.8" cy="87.4" r=".3"/>
<circle cx="166.7" cy="85.6" r=".3"/>
<circle cx="140.2" cy="86.2" r=".3"/>
<circle cx="160.2" cy="111" r=".3"/>
<circle cx="149.2" cy="89.2" r=".3"/>
<circle cx="136" cy="85.6" r=".3"/>
<circle cx="132.4" cy="85.6" r=".3"/>
<circle cx="145.6" cy="88" r=".3"/>
<circle cx="147" cy="111.6" r=".3"/>
<circle cx="150" cy="110.4" r=".3"/>
<circle cx="126" cy="111.6" r=".3"/>
<circle cx="141.6" cy="110.4" r=".3"/>
<circle cx="136" cy="90.4" r=".3"/>
<circle cx="154" cy="87.4" r=".3"/>
<circle cx="154.6" cy="85.6" r=".3"/>
<circle cx="135" cy="111" r=".3"/>
<circle cx="155.4" cy="107.4" r=".3"/>
<circle cx="141.6" cy="109.2" r=".3"/>
<circle cx="144" cy="111.6" r=".3"/>
<circle cx="158.8" cy="88.6" r=".3"/>
<circle cx="144.4" cy="86.8" r=".3"/>
<circle cx="147.4" cy="85.6" r=".3"/>
<circle cx="141" cy="108" r=".3"/>
<circle cx="136.2" cy="111.6" r=".3"/>
<circle cx="154.2" cy="109.2" r=".3"/>
<circle cx="129.4" cy="91" r=".3"/>
<circle cx="131.4" cy="106.8" r=".3"/>
<circle cx="143.8" cy="85.6" r=".3"/>
<circle cx="137.4" cy="111.6" r=".3"/>
<circle cx="161.2" cy="89.2" r=".3"/>
<circle cx="154.2" cy="111.6" r=".3"/>
<circle cx="151.8" cy="92.4" r=".3"/>
<circle cx="139.2" cy="108" r=".3"/>
<circle cx="140.4" cy="111.6" r=".3"/>
<circle cx="133" cy="86.2" r=".3"/>
<circle cx="158.4" cy="111" r=".3"/>
<circle cx="159.6" cy="109.8" r=".3"/>
<circle cx="142.9" cy="104.2" r=".3"/>
<circle cx="146.3" cy="100.2" r=".3"/>
<circle cx="149.8" cy="103.4" r=".3"/>
<circle cx="127.1" cy="101.4" r=".3"/>
<circle cx="127.1" cy="100.6" r=".3"/>
<circle cx="126.9" cy="97" r=".3"/>
<circle cx="126.9" cy="96.1" r=".3"/>
<circle cx="164.2" cy="102.6" r=".3"/>
<circle cx="148.8" cy="90.4" r=".3"/>
<circle cx="164.2" cy="100.1" r=".3"/>
<circle cx="146.2" cy="92.7" r=".3"/>
<circle cx="146.6" cy="91.8" r=".3"/>
<circle cx="164.2" cy="98.2" r=".3"/>
<circle cx="164.2" cy="101.2" r=".3"/>
<circle cx="143.8" cy="90.4" r=".3"/>
<circle cx="154.1" cy="96" r=".3"/>
<circle cx="153.6" cy="98.8" r=".3"/>
<circle cx="142" cy="92.3" r=".3"/>
<circle cx="147.6" cy="96" r=".3"/>
<circle cx="148.4" cy="96" r=".3"/>
<circle cx="142.3" cy="91.6" r=".3"/>
<circle cx="132.5" cy="95.7" r=".3"/>
<circle cx="132.5" cy="97.5" r=".3"/>
<circle cx="130.7" cy="101.5" r=".3"/>
<circle cx="131" cy="100.7" r=".3"/>
<circle cx="160.2" cy="102.8" r=".3"/>
<circle cx="160.2" cy="101.6" r=".3"/>
<circle cx="160.3" cy="100.1" r=".3"/>
<circle cx="160.4" cy="98.2" r=".3"/>
<circle cx="127.9" cy="99.2" r=".3"/>
</g>
<path d="M125.2 84.5l42.3-.1 .1 .1-.1 27.7h-42.2l-.1-2.8h2a1.35 1.35 0 0 0 1.3 1.5 1.35 1.35 0 0 0 1.5-1.4h32.4v.2a1.35 1.35 0 0 0 2.1 1.1 1.35 1.35 0 0 0 0-2.4 1.35 1.35 0 0 0-2.1 1.1l-32.4-.1a1.35 1.35 0 0 0-1.4-1.3 1.35 1.35 0 0 0-1.4 1.3h-2v-5.2h16.9v.2a.81 .81 0 0 0 1.3 .4 .81 .81 0 0 0-.1-1.3 .81 .81 0 0 0-1.2 .7h-16.9v-.8h23.7l.1 .1a.8 .8 0 0 0 1.1 .6 .8 .8 0 0 0 .2-1.3h9.1v.2a.84 .84 0 0 0 1.3 .4 .84 .84 0 0 0 .2-1.3l.2-.5-.2-.4h2.5l.3 .8a.83 .83 0 0 0 0 1.2 .83 .83 0 0 0 1.2-.2 .83 .83 0 0 0-.2-1.2 1.1 1.1 0 0 0 .1-1.2 .84 .84 0 0 0-.1-1.2 .84 .84 0 0 0-1.2 .2 .84 .84 0 0 0 0 1.1l-.1 .5h-2.5l-.3-.3a.91 .91 0 0 0 .5-.9 .91 .91 0 0 0-.6-.7 .85 .85 0 0 0-1 .5 .85 .85 0 0 0 .4 1v.1a1.07 1.07 0 0 0-.3 1.4l-.2 .5-9.1-.1a.81 .81 0 0 0-.9-.1 .81 .81 0 0 0-.5 .8h-23.7v-2.8h1.1l.1 .3a.83 .83 0 0 0 .4 1.3 .83 .83 0 0 0 1.1-.7h2v.2a.83 .83 0 0 0 1 .6 .83 .83 0 0 0 .6-1l.3-.6-.2-.5h13.8l.1 .2a.81 .81 0 0 0 1.3 .5 .81 .81 0 0 0-.2-1.4 .81 .81 0 0 0-1.2 .7h-13.8l-.1-.1a.91 .91 0 0 0-1 0 .91 .91 0 0 0-.4 .9l-.2 .5h-2l-.1-1.4a.96 .96 0 0 0 .8-1.3h24.2v.2a.8 .8 0 0 0 1.2 .5 .8 .8 0 0 0 .1-1.3h5.5v.2a.81 .81 0 0 0 .9 .6 .81 .81 0 0 0 .7-.8h2.2l.1 .2a.81 .81 0 0 0 1.3 .4 .81 .81 0 0 0-.2-1.3 .81 .81 0 0 0-1.2 .7h-2.2a.81 .81 0 0 0-.8-.8 .81 .81 0 0 0-.8 .8l-5.5-.1a.81 .81 0 0 0-.9-.1 .81 .81 0 0 0-.4 .8l-24.2-.1a.84 .84 0 0 0-1.2-.1 .84 .84 0 0 0-.2 1.1l-.6 .2-.3 .7h-1.1v-4.5h.9v.4a.85 .85 0 0 0 .3 1 .85 .85 0 0 0 1.1 0h4.2v.2a.84 .84 0 0 0 1.5 .3 .84 .84 0 0 0-.6-1.4l.7-.6h13.5a.85 .85 0 0 0 1.3 .7h.6a.58 .58 0 0 1 .9 0l.5-.2 .3-.5h2.9a.81 .81 0 0 0 1.2 .7 .81 .81 0 0 0 .1-1.3 .81 .81 0 0 0-1.3 .4v.2h-2.9a.87 .87 0 0 0-.5-.9 .87 .87 0 0 0-1 .3l-.5-.2-.4 .1a.88 .88 0 0 0-1.2 .7h-13.5v-.1a.83 .83 0 0 0-.7-1 .83 .83 0 0 0-.9 .7 .83 .83 0 0 0 .7 1l-.5 .4-.2 .5h-4.2l.2-.4-.1-.5a.83 .83 0 0 0-.5-1.2 .83 .83 0 0 0-1 .7h-.9v-3.8h16v.2a.8 .8 0 0 0 .7 .6 .8 .8 0 0 0 .8-.4h2.7l.1 .2a.85 .85 0 0 0 1 .6 .85 .85 0 0 0 .6-1.1 .84 .84 0 0 0-.4-1.4 .84 .84 0 0 0-1 1.1l-.3 .6h-2.7l.2-.6a1.24 1.24 0 0 0 1.1-.9l.4-.3 .2-.5h3.4a.81 .81 0 0 0 1.1 .7 .81 .81 0 0 0 .2-1.3 .81 .81 0 0 0-1.3 .4v.2h-3.4a.86 .86 0 0 0-.9-.8 .86 .86 0 0 0-.8 .9l-.6 .3a1 1 0 0 0-.9 1l-.2 .5h-16v-5.2h2.3a1.35 1.35 0 0 0 1.4 1.5 1.35 1.35 0 0 0 1.3-1.6h32.4v.2a1.35 1.35 0 0 0 2.1 1.1 1.35 1.35 0 0 0 0-2.4 1.35 1.35 0 0 0-2.1 1.1h-32.4v-.1a1.35 1.35 0 0 0-1.4-1.1 1.35 1.35 0 0 0-1.3 1.3h-2.3z" fill="#ce7d2c"/>
</svg>
